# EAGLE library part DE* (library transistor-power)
RF Power MOSFET DE-SERIES Source: http://www.ixysrf.com/pdf/switch_mode/appnotes/2de_series_intro.pdf

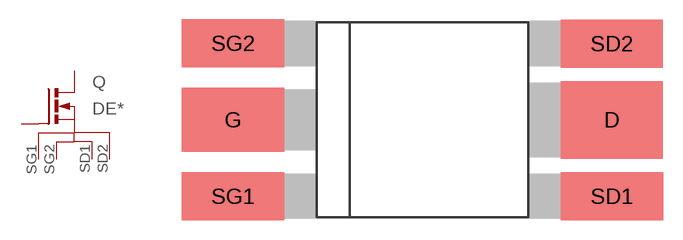
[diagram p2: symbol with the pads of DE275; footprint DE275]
Designator prefix Q

## DE150-102N02A, DE150-201N09A, DE150-501N04A, DE275-101N30, DE275-102N06A, DE275-201N25A, DE275-501N16A, DE375-102N10A, DE375-102N12A, DE375-501N21A, DE475-102N20A, DE475-501N16A, DE475-501N44A  [DE275]
D  D  pas
G  G  pas
SD1  SD1  pas
SD2  SD2  pas
SG1  SG1  pas
SG2  SG2  pas

## Footprint DE275 (pad centres in mm)
DE-275 Package Source: http://ixysrf.com/pdf/switch_mode/appnotes/2de_series_intro.pdf
smd 7.874 x 5.969: D 14.592,0
smd 7.874 x 4.953: G -14.592,0
smd 7.874 x 3.683: SD1 14.605,-5.893; SD2 14.592,5.867; SG1 -14.592,-5.893; SG2 -14.592,5.893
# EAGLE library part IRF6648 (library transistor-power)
DirectFET Power MOSFET Source: http://www.irf.com/product-info/datasheets/data/irf6648.pdf

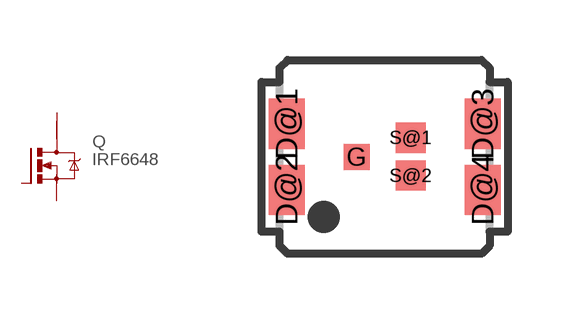
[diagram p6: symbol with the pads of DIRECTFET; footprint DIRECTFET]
Designator prefix Q

## IRF6648  [DIRECTFET]
D@1  D  pas
D@2  D  pas
D@3  D  pas
D@4  D  pas
G  G  pas
S@1  S  pas
S@2  S  pas

## Footprint DIRECTFET (pad centres in mm)
DirectFET (TM) Outline Dimension, MN Outline (Medium Size Can, N-Designation). Source: http://www.irf.com/product-info/datasheets/data/irf6648.pdf
smd 0.9 x 1.25: D@1 -2.45,0.825; D@2 -2.45,-0.825; D@3 2.45,0.825; D@4 2.45,-0.825
smd 0.65 x 0.65: G -0.7,0
smd 0.75 x 0.75: S@1 0.65,0.475; S@2 0.65,-0.475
